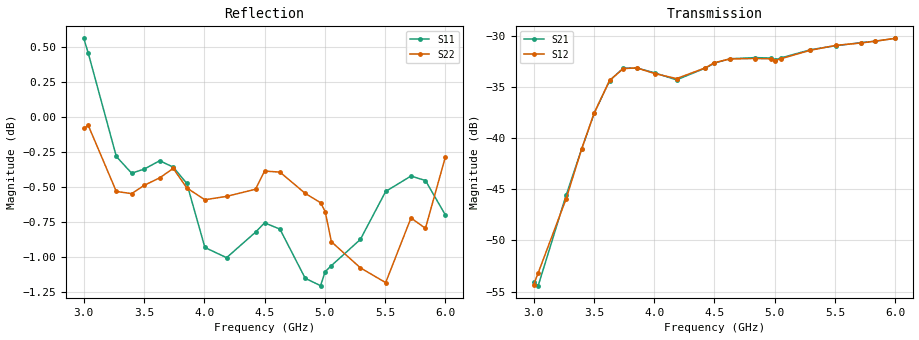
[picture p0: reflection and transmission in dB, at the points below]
!  26/11/2025  18:01:05
! Ref Plane: 0.000 mm
# MHZ S MA R  50
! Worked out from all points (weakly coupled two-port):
!   401 points, 3 GHz to 6 GHz, reference 50 ohm
!   highest |S21| = -30.24 dB at 6 GHz (marker M1); lowest = -54.4 dB at 3.038 GHz (marker M2)
!   lowest |S11| = -1.2 dB at 4.965 GHz (marker M3), VSWR 14.44, Z = 7.53 - j53.9 ohm
!   |S11| at or under -10 dB: nowhere
!   |S22| runs from -1.2 to 0.0 dB; largest |S21 - S12| = 0.0012
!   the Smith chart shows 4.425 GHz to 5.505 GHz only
!   S11 on the Smith chart (normalised r, x): 4.425 GHz: 0.10, +1.03; 4.628 GHz: 1.19, +4.85; 4.838 GHz: 0.43, -2.32; 5.055 GHz: 0.09, -0.68; 5.295 GHz: 0.05, -0.03; 5.505 GHz: 0.04, +0.59
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3000  1.067 -136.6  0.001975 41.0  0.001925 45.4  0.9909 -105.1
3037.5  1.054 -146.4  0.0019 33.0  0.002196 38.6  0.9932 -110.6
3270  0.9682 152.8  0.005285 -26.4  0.00507 -21.5  0.9407 -169.6
3397.5  0.9549 109.2  0.008826 -65.9  0.008842 -65.4  0.939 151.8
3502.5  0.9582 66.1  0.01328 -107.2  0.01329 -106.3  0.9455 114.0
3630  0.9648 10.8  0.01912 -164.1  0.01916 -163.0  0.9513 59.5
3742.5  0.9597 -39.0  0.02196 144.7  0.02187 146.0  0.9587 11.7
3855  0.9469 -84.4  0.02204 97.2  0.02207 98.2  0.9434 -34.1
4005  0.8983 -138.2  0.02085 42.2  0.02069 43.1  0.9343 -86.2
4185  0.8908 164.7  0.01928 -11.1  0.01956 -9.1  0.9369 -142.8
4425  0.9097 87.8  0.02202 -78.3  0.02208 -76.9  0.9424 143.9
4500  0.9167 63.5  0.02328 -101.8  0.0234 -100.5  0.9566 121.0
4627.5  0.912 22.0  0.02445 -142.0  0.02439 -140.9  0.9558 81.8
4837.5  0.8758 -45.5  0.02477 153.5  0.02452 155.1  0.9392 18.4
4965  0.8705 -85.1  0.02465 118.2  0.02443 119.5  0.932 -17.8
5002.5  0.8806 -96.5  0.02415 107.9  0.02395 109.2  0.9253 -29.8
5055  0.885 -111.5  0.02471 93.3  0.02449 93.9  0.9025 -45.4
5295  0.9043 -176.7  0.02705 27.2  0.0269 28.7  0.8834 -112.6
5505  0.9407 119.3  0.02832 -33.1  0.02842 -31.3  0.8727 -170.7
5715  0.9527 60.0  0.0293 -93.7  0.0292 -91.5  0.9204 129.5
5835  0.9492 24.1  0.0298 -129.2  0.02981 -127.2  0.9126 96.4
6000  0.9227 -22.7  0.03076 -175.4  0.03076 -174.0  0.9677 55.9
